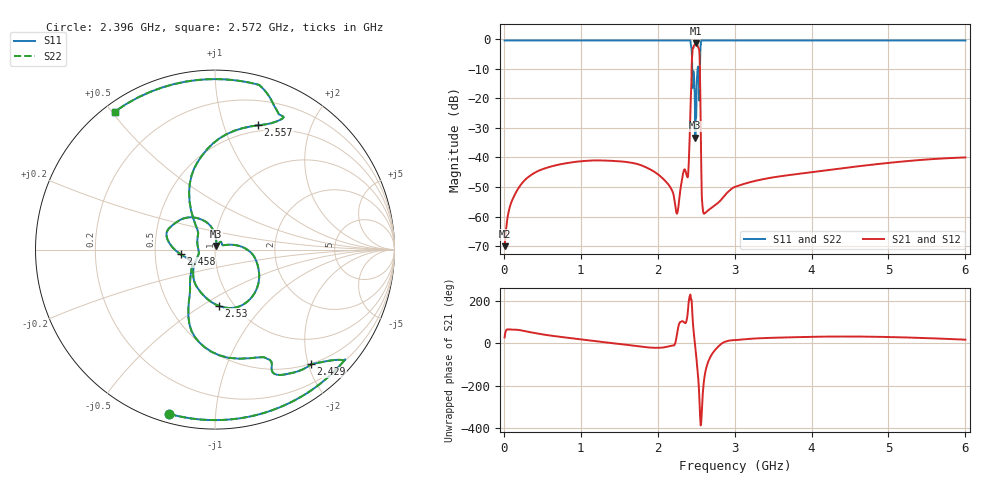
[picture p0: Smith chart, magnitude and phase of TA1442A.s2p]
! Project 16: active antenna, S-band (NavIC) branch (RFMW-ANT)
! Generated by Scripts/sband.py from Scripts/ds_data.py; format GHz / RI, Z0 = 50 ohm
! ESTIMATED from Tai-Saw TA1442A product specification approval sheet, rev. 1, 2011-12-19: |S21| digitized from the VNA plots p.3 (marker values exact),
! VSWR from p.4; phase = minimum-phase reconstruction; arg S11 = arg S22 = arg S21 + 90 deg. NOT measured data.
# GHz S RI R 50.0
!freq ReS11 ImS11 ReS21 ImS21 ReS12 ImS12 ReS22 ImS22
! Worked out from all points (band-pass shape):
!   11981 points, 10 MHz to 6 GHz, reference 50 ohm
!   highest |S21| = -1.45 dB at 2.5 GHz (marker M1); lowest = -70.0 dB at 10 MHz (marker M2)
!   |S21| within 3 dB of the highest: 2.451 GHz to 2.542 GHz (91.31 MHz wide, 3.66 % of centre)
!   lowest |S11| = -33.3 dB at 2.49 GHz (marker M3), VSWR 1.04, Z = 50.7 + j2.04 ohm
!   |S11| at or under -10 dB: 2.448 GHz to 2.519 GHz (71.4 MHz wide, 2.87 % of centre); 2.529 GHz to 2.55 GHz (20.33 MHz wide, 0.801 % of centre)
!   |S22| runs from -32.3 to -0.4 dB; largest |S21 - S12| = 0
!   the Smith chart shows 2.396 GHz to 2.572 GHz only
!   S11 on the Smith chart (normalised r, x): 2.396 GHz: 0.04, -0.76; 2.429 GHz: 0.49, -2.05; 2.458 GHz: 0.68, -0.04; 2.53 GHz: 0.85, -0.59; 2.557 GHz: 0.44, +1.31; 2.572 GHz: 0.03, +0.51
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0.01  -0.4413 0.8413  0.00028 0.000147  0.00028 0.000147  -0.4413 0.8413
0.2685  -0.8035 0.5068  0.00218 0.00346  0.00218 0.00346  -0.8035 0.5068
1.0085  -0.2936 0.9034  0.00821 0.00267  0.00821 0.00267  -0.2936 0.9034
2.007  0.346 0.8847  0.00479 -0.00187  0.00479 -0.00187  0.346 0.8847
2.2195  0.115 0.943  0.0018 -0.000219  0.0018 -0.000219  0.115 0.943
2.2895  -0.9385 -0.1471  -0.00039 0.00249  -0.00039 0.00249  -0.9385 -0.1471
2.362  -0.9454 -0.0929  -0.000577 0.00587  -0.000577 0.00587  -0.9454 -0.0929
2.3955  -0.2555 -0.915  -0.0049 0.00137  -0.0049 0.00137  -0.2555 -0.915
2.429  0.535 -0.6389  -0.07 -0.0586  -0.07 -0.0586  0.535 -0.6389
2.4575  -0.1907 -0.0266  -0.0983 0.705  -0.0983 0.705  -0.1907 -0.0266
2.4895  0.00759 0.0201  0.7821 -0.2947  0.7821 -0.2947  0.0086 0.0228
2.5  0.0402 0.0255  0.4532 -0.7147  0.4532 -0.7147  0.0402 0.0255
2.5295  0.0211 -0.3132  -0.7086 -0.0477  -0.7086 -0.0477  0.0211 -0.3132
2.5565  0.2402 0.6927  0.0673 -0.0233  0.0673 -0.0233  0.2402 0.6927
2.5725  -0.5594 0.7679  0.00198 0.00144  0.00198 0.00144  -0.5594 0.7679
2.6115  0.4551 -0.8339  -0.000996 -0.000543  -0.000996 -0.000543  0.4551 -0.8339
2.659  0.9461 0.0855  0.000116 -0.00128  0.000116 -0.00128  0.9461 0.0855
2.7685  0.3602 0.8791  0.00152 -0.000623  0.00152 -0.000623  0.3602 0.8791
3.005  -0.2454 0.9178  0.00307 0.000821  0.00307 0.000821  -0.2454 0.9178
4.0035  -0.4836 0.8177  0.00485 0.00287  0.00485 0.00287  -0.4836 0.8177
5.002  -0.4694 0.8259  0.00704 0.004  0.00704 0.004  -0.4694 0.8259
6  -0.2784 0.9082  0.00956 0.00293  0.00956 0.00293  -0.2784 0.9082
